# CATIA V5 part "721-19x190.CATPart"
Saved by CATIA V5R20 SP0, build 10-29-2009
Part number: 721-19x190
Definition: NONE
Nomenclature: 721-19x190
Source: Unknown
Description: 721-19x190
Bounding box of the stored display mesh (mm): x -80 to 110, y -21 to 21, z -21 to 21
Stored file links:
  C:\Users\Utente\Desktop\IO LAVORO\3D X SITO CF\X SITO\721\721-19x190.CATPart

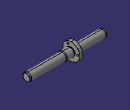
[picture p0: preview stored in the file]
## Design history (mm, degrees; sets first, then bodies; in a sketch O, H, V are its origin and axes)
Body1 "721-19x190" (main body)
  Solid1: solid without history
